# sr16_rx4_integ.lef : copie de sr16_rx4.lef pour l integration de MSPHY5973 (prompt-063-leo, 29/09/2026).
# Seul changement : CK_P et CK_N elargies de x 0,15 a 0,40 um vers l interieur, dans le couloir Metal3
# libre d obstruction (0 a 0,63 um). Le fil du routeur recouvre alors la vraie borne (0 a 0,15). Sans cela :
# DRT-0073 No access point for sr16_rx4/CK_N (coupe4). A remonter au generateur (Caelum).
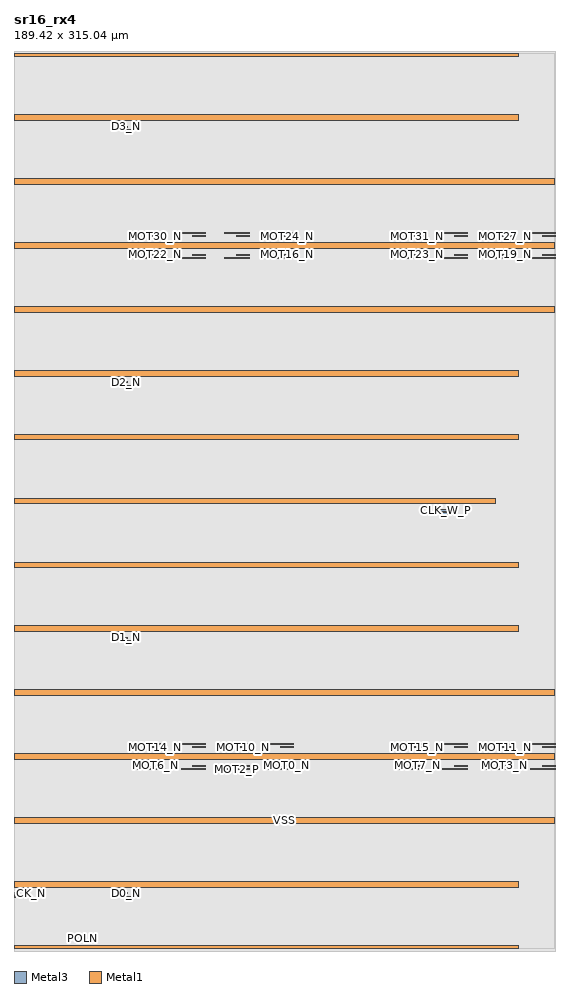
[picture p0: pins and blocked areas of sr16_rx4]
MACRO sr16_rx4
  CLASS BLOCK ;
  FOREIGN sr16_rx4 ;
  ORIGIN 0.150 1.000 ;
  SIZE 189.420 BY 315.040 ;
  PIN CK_N
    DIRECTION INPUT ;
    USE SIGNAL ;
    PORT
      LAYER Metal3 ;
        RECT 0.000 18.760 0.400 19.360 ;
    END
  END CK_N
  PIN CK_P
    DIRECTION INPUT ;
    USE SIGNAL ;
    PORT
      LAYER Metal3 ;
        RECT 0.000 17.660 0.400 18.260 ;
    END
  END CK_P
  PIN D0_N
    DIRECTION INPUT ;
    USE SIGNAL ;
    PORT
      LAYER Metal3 ;
        RECT 38.170 19.010 39.735 19.310 ;
    END
  END D0_N
  PIN D0_P
    DIRECTION INPUT ;
    USE SIGNAL ;
    PORT
      LAYER Metal3 ;
        RECT 38.170 17.910 41.980 18.210 ;
    END
  END D0_P
  PIN D1_N
    DIRECTION INPUT ;
    USE SIGNAL ;
    PORT
      LAYER Metal3 ;
        RECT 38.170 108.450 39.735 108.750 ;
    END
  END D1_N
  PIN D1_P
    DIRECTION INPUT ;
    USE SIGNAL ;
    PORT
      LAYER Metal3 ;
        RECT 38.170 107.350 41.980 107.650 ;
    END
  END D1_P
  PIN D2_N
    DIRECTION INPUT ;
    USE SIGNAL ;
    PORT
      LAYER Metal3 ;
        RECT 38.170 197.890 39.735 198.190 ;
    END
  END D2_N
  PIN D2_P
    DIRECTION INPUT ;
    USE SIGNAL ;
    PORT
      LAYER Metal3 ;
        RECT 38.170 196.790 41.980 197.090 ;
    END
  END D2_P
  PIN D3_N
    DIRECTION INPUT ;
    USE SIGNAL ;
    PORT
      LAYER Metal3 ;
        RECT 38.170 287.330 39.735 287.630 ;
    END
  END D3_N
  PIN D3_P
    DIRECTION INPUT ;
    USE SIGNAL ;
    PORT
      LAYER Metal3 ;
        RECT 38.170 286.230 41.980 286.530 ;
    END
  END D3_P
  PIN POLN
    DIRECTION INPUT ;
    USE SIGNAL ;
    PORT
      LAYER Metal3 ;
        RECT 23.370 3.010 24.040 4.030 ;
    END
  END POLN
  PIN MOT0_N
    DIRECTION OUTPUT ;
    USE SIGNAL ;
    PORT
      LAYER Metal3 ;
        RECT 93.050 63.480 97.590 64.080 ;
    END
  END MOT0_N
  PIN MOT0_P
    DIRECTION OUTPUT ;
    USE SIGNAL ;
    PORT
      LAYER Metal3 ;
        RECT 89.030 62.380 97.590 62.980 ;
    END
  END MOT0_P
  PIN MOT1_N
    DIRECTION OUTPUT ;
    USE SIGNAL ;
    PORT
      LAYER Metal3 ;
        RECT 184.730 63.480 189.270 64.080 ;
    END
  END MOT1_N
  PIN MOT1_P
    DIRECTION OUTPUT ;
    USE SIGNAL ;
    PORT
      LAYER Metal3 ;
        RECT 180.710 62.380 189.270 62.980 ;
    END
  END MOT1_P
  PIN MOT2_N
    DIRECTION OUTPUT ;
    USE SIGNAL ;
    PORT
      LAYER Metal3 ;
        RECT 77.690 63.480 82.230 64.080 ;
    END
  END MOT2_N
  PIN MOT2_P
    DIRECTION OUTPUT ;
    USE SIGNAL ;
    PORT
      LAYER Metal3 ;
        RECT 73.670 62.380 82.230 62.980 ;
    END
  END MOT2_P
  PIN MOT3_N
    DIRECTION OUTPUT ;
    USE SIGNAL ;
    PORT
      LAYER Metal3 ;
        RECT 169.370 63.480 173.910 64.080 ;
    END
  END MOT3_N
  PIN MOT3_P
    DIRECTION OUTPUT ;
    USE SIGNAL ;
    PORT
      LAYER Metal3 ;
        RECT 165.350 62.380 173.910 62.980 ;
    END
  END MOT3_P
  PIN MOT4_N
    DIRECTION OUTPUT ;
    USE SIGNAL ;
    PORT
      LAYER Metal3 ;
        RECT 62.330 63.480 66.870 64.080 ;
    END
  END MOT4_N
  PIN MOT4_P
    DIRECTION OUTPUT ;
    USE SIGNAL ;
    PORT
      LAYER Metal3 ;
        RECT 58.310 62.380 66.870 62.980 ;
    END
  END MOT4_P
  PIN MOT5_N
    DIRECTION OUTPUT ;
    USE SIGNAL ;
    PORT
      LAYER Metal3 ;
        RECT 154.010 63.480 158.550 64.080 ;
    END
  END MOT5_N
  PIN MOT5_P
    DIRECTION OUTPUT ;
    USE SIGNAL ;
    PORT
      LAYER Metal3 ;
        RECT 149.990 62.380 158.550 62.980 ;
    END
  END MOT5_P
  PIN MOT6_N
    DIRECTION OUTPUT ;
    USE SIGNAL ;
    PORT
      LAYER Metal3 ;
        RECT 46.970 63.480 51.510 64.080 ;
    END
  END MOT6_N
  PIN MOT6_P
    DIRECTION OUTPUT ;
    USE SIGNAL ;
    PORT
      LAYER Metal3 ;
        RECT 42.950 62.380 51.510 62.980 ;
    END
  END MOT6_P
  PIN MOT7_N
    DIRECTION OUTPUT ;
    USE SIGNAL ;
    PORT
      LAYER Metal3 ;
        RECT 138.650 63.480 143.190 64.080 ;
    END
  END MOT7_N
  PIN MOT7_P
    DIRECTION OUTPUT ;
    USE SIGNAL ;
    PORT
      LAYER Metal3 ;
        RECT 134.630 62.380 143.190 62.980 ;
    END
  END MOT7_P
  PIN MOT8_N
    DIRECTION OUTPUT ;
    USE SIGNAL ;
    PORT
      LAYER Metal3 ;
        RECT 93.050 70.080 97.590 70.680 ;
    END
  END MOT8_N
  PIN MOT8_P
    DIRECTION OUTPUT ;
    USE SIGNAL ;
    PORT
      LAYER Metal3 ;
        RECT 89.030 71.180 97.590 71.780 ;
    END
  END MOT8_P
  PIN MOT9_N
    DIRECTION OUTPUT ;
    USE SIGNAL ;
    PORT
      LAYER Metal3 ;
        RECT 184.730 70.080 189.270 70.680 ;
    END
  END MOT9_N
  PIN MOT9_P
    DIRECTION OUTPUT ;
    USE SIGNAL ;
    PORT
      LAYER Metal3 ;
        RECT 180.710 71.180 189.270 71.780 ;
    END
  END MOT9_P
  PIN MOT10_N
    DIRECTION OUTPUT ;
    USE SIGNAL ;
    PORT
      LAYER Metal3 ;
        RECT 77.690 70.080 82.230 70.680 ;
    END
  END MOT10_N
  PIN MOT10_P
    DIRECTION OUTPUT ;
    USE SIGNAL ;
    PORT
      LAYER Metal3 ;
        RECT 73.670 71.180 82.230 71.780 ;
    END
  END MOT10_P
  PIN MOT11_N
    DIRECTION OUTPUT ;
    USE SIGNAL ;
    PORT
      LAYER Metal3 ;
        RECT 169.370 70.080 173.910 70.680 ;
    END
  END MOT11_N
  PIN MOT11_P
    DIRECTION OUTPUT ;
    USE SIGNAL ;
    PORT
      LAYER Metal3 ;
        RECT 165.350 71.180 173.910 71.780 ;
    END
  END MOT11_P
  PIN MOT12_N
    DIRECTION OUTPUT ;
    USE SIGNAL ;
    PORT
      LAYER Metal3 ;
        RECT 62.330 70.080 66.870 70.680 ;
    END
  END MOT12_N
  PIN MOT12_P
    DIRECTION OUTPUT ;
    USE SIGNAL ;
    PORT
      LAYER Metal3 ;
        RECT 58.310 71.180 66.870 71.780 ;
    END
  END MOT12_P
  PIN MOT13_N
    DIRECTION OUTPUT ;
    USE SIGNAL ;
    PORT
      LAYER Metal3 ;
        RECT 154.010 70.080 158.550 70.680 ;
    END
  END MOT13_N
  PIN MOT13_P
    DIRECTION OUTPUT ;
    USE SIGNAL ;
    PORT
      LAYER Metal3 ;
        RECT 149.990 71.180 158.550 71.780 ;
    END
  END MOT13_P
  PIN MOT14_N
    DIRECTION OUTPUT ;
    USE SIGNAL ;
    PORT
      LAYER Metal3 ;
        RECT 46.970 70.080 51.510 70.680 ;
    END
  END MOT14_N
  PIN MOT14_P
    DIRECTION OUTPUT ;
    USE SIGNAL ;
    PORT
      LAYER Metal3 ;
        RECT 42.950 71.180 51.510 71.780 ;
    END
  END MOT14_P
  PIN MOT15_N
    DIRECTION OUTPUT ;
    USE SIGNAL ;
    PORT
      LAYER Metal3 ;
        RECT 138.650 70.080 143.190 70.680 ;
    END
  END MOT15_N
  PIN MOT15_P
    DIRECTION OUTPUT ;
    USE SIGNAL ;
    PORT
      LAYER Metal3 ;
        RECT 134.630 71.180 143.190 71.780 ;
    END
  END MOT15_P
  PIN MOT16_N
    DIRECTION OUTPUT ;
    USE SIGNAL ;
    PORT
      LAYER Metal3 ;
        RECT 93.050 242.360 97.590 242.960 ;
    END
  END MOT16_N
  PIN MOT16_P
    DIRECTION OUTPUT ;
    USE SIGNAL ;
    PORT
      LAYER Metal3 ;
        RECT 89.030 241.260 97.590 241.860 ;
    END
  END MOT16_P
  PIN MOT17_N
    DIRECTION OUTPUT ;
    USE SIGNAL ;
    PORT
      LAYER Metal3 ;
        RECT 184.730 242.360 189.270 242.960 ;
    END
  END MOT17_N
  PIN MOT17_P
    DIRECTION OUTPUT ;
    USE SIGNAL ;
    PORT
      LAYER Metal3 ;
        RECT 180.710 241.260 189.270 241.860 ;
    END
  END MOT17_P
  PIN MOT18_N
    DIRECTION OUTPUT ;
    USE SIGNAL ;
    PORT
      LAYER Metal3 ;
        RECT 77.690 242.360 82.230 242.960 ;
    END
  END MOT18_N
  PIN MOT18_P
    DIRECTION OUTPUT ;
    USE SIGNAL ;
    PORT
      LAYER Metal3 ;
        RECT 73.670 241.260 82.230 241.860 ;
    END
  END MOT18_P
  PIN MOT19_N
    DIRECTION OUTPUT ;
    USE SIGNAL ;
    PORT
      LAYER Metal3 ;
        RECT 169.370 242.360 173.910 242.960 ;
    END
  END MOT19_N
  PIN MOT19_P
    DIRECTION OUTPUT ;
    USE SIGNAL ;
    PORT
      LAYER Metal3 ;
        RECT 165.350 241.260 173.910 241.860 ;
    END
  END MOT19_P
  PIN MOT20_N
    DIRECTION OUTPUT ;
    USE SIGNAL ;
    PORT
      LAYER Metal3 ;
        RECT 62.330 242.360 66.870 242.960 ;
    END
  END MOT20_N
  PIN MOT20_P
    DIRECTION OUTPUT ;
    USE SIGNAL ;
    PORT
      LAYER Metal3 ;
        RECT 58.310 241.260 66.870 241.860 ;
    END
  END MOT20_P
  PIN MOT21_N
    DIRECTION OUTPUT ;
    USE SIGNAL ;
    PORT
      LAYER Metal3 ;
        RECT 154.010 242.360 158.550 242.960 ;
    END
  END MOT21_N
  PIN MOT21_P
    DIRECTION OUTPUT ;
    USE SIGNAL ;
    PORT
      LAYER Metal3 ;
        RECT 149.990 241.260 158.550 241.860 ;
    END
  END MOT21_P
  PIN MOT22_N
    DIRECTION OUTPUT ;
    USE SIGNAL ;
    PORT
      LAYER Metal3 ;
        RECT 46.970 242.360 51.510 242.960 ;
    END
  END MOT22_N
  PIN MOT22_P
    DIRECTION OUTPUT ;
    USE SIGNAL ;
    PORT
      LAYER Metal3 ;
        RECT 42.950 241.260 51.510 241.860 ;
    END
  END MOT22_P
  PIN MOT23_N
    DIRECTION OUTPUT ;
    USE SIGNAL ;
    PORT
      LAYER Metal3 ;
        RECT 138.650 242.360 143.190 242.960 ;
    END
  END MOT23_N
  PIN MOT23_P
    DIRECTION OUTPUT ;
    USE SIGNAL ;
    PORT
      LAYER Metal3 ;
        RECT 134.630 241.260 143.190 241.860 ;
    END
  END MOT23_P
  PIN MOT24_N
    DIRECTION OUTPUT ;
    USE SIGNAL ;
    PORT
      LAYER Metal3 ;
        RECT 93.050 248.960 97.590 249.560 ;
    END
  END MOT24_N
  PIN MOT24_P
    DIRECTION OUTPUT ;
    USE SIGNAL ;
    PORT
      LAYER Metal3 ;
        RECT 89.030 250.060 97.590 250.660 ;
    END
  END MOT24_P
  PIN MOT25_N
    DIRECTION OUTPUT ;
    USE SIGNAL ;
    PORT
      LAYER Metal3 ;
        RECT 184.730 248.960 189.270 249.560 ;
    END
  END MOT25_N
  PIN MOT25_P
    DIRECTION OUTPUT ;
    USE SIGNAL ;
    PORT
      LAYER Metal3 ;
        RECT 180.710 250.060 189.270 250.660 ;
    END
  END MOT25_P
  PIN MOT26_N
    DIRECTION OUTPUT ;
    USE SIGNAL ;
    PORT
      LAYER Metal3 ;
        RECT 77.690 248.960 82.230 249.560 ;
    END
  END MOT26_N
  PIN MOT26_P
    DIRECTION OUTPUT ;
    USE SIGNAL ;
    PORT
      LAYER Metal3 ;
        RECT 73.670 250.060 82.230 250.660 ;
    END
  END MOT26_P
  PIN MOT27_N
    DIRECTION OUTPUT ;
    USE SIGNAL ;
    PORT
      LAYER Metal3 ;
        RECT 169.370 248.960 173.910 249.560 ;
    END
  END MOT27_N
  PIN MOT27_P
    DIRECTION OUTPUT ;
    USE SIGNAL ;
    PORT
      LAYER Metal3 ;
        RECT 165.350 250.060 173.910 250.660 ;
    END
  END MOT27_P
  PIN MOT28_N
    DIRECTION OUTPUT ;
    USE SIGNAL ;
    PORT
      LAYER Metal3 ;
        RECT 62.330 248.960 66.870 249.560 ;
    END
  END MOT28_N
  PIN MOT28_P
    DIRECTION OUTPUT ;
    USE SIGNAL ;
    PORT
      LAYER Metal3 ;
        RECT 58.310 250.060 66.870 250.660 ;
    END
  END MOT28_P
  PIN MOT29_N
    DIRECTION OUTPUT ;
    USE SIGNAL ;
    PORT
      LAYER Metal3 ;
        RECT 154.010 248.960 158.550 249.560 ;
    END
  END MOT29_N
  PIN MOT29_P
    DIRECTION OUTPUT ;
    USE SIGNAL ;
    PORT
      LAYER Metal3 ;
        RECT 149.990 250.060 158.550 250.660 ;
    END
  END MOT29_P
  PIN MOT30_N
    DIRECTION OUTPUT ;
    USE SIGNAL ;
    PORT
      LAYER Metal3 ;
        RECT 46.970 248.960 51.510 249.560 ;
    END
  END MOT30_N
  PIN MOT30_P
    DIRECTION OUTPUT ;
    USE SIGNAL ;
    PORT
      LAYER Metal3 ;
        RECT 42.950 250.060 51.510 250.660 ;
    END
  END MOT30_P
  PIN MOT31_N
    DIRECTION OUTPUT ;
    USE SIGNAL ;
    PORT
      LAYER Metal3 ;
        RECT 138.650 248.960 143.190 249.560 ;
    END
  END MOT31_N
  PIN MOT31_P
    DIRECTION OUTPUT ;
    USE SIGNAL ;
    PORT
      LAYER Metal3 ;
        RECT 134.630 250.060 143.190 250.660 ;
    END
  END MOT31_P
  PIN CLK_W_N
    DIRECTION OUTPUT ;
    USE SIGNAL ;
    PORT
      LAYER Metal3 ;
        RECT 144.630 151.820 153.190 152.420 ;
    END
  END CLK_W_N
  PIN CLK_W_P
    DIRECTION OUTPUT ;
    USE SIGNAL ;
    PORT
      LAYER Metal3 ;
        RECT 148.650 152.920 153.190 153.520 ;
    END
  END CLK_W_P
  PIN VDD
    DIRECTION INOUT ;
    USE POWER ;
    PORT
      LAYER Metal1 ;
        RECT 0.000 21.360 176.560 23.360 ;
        RECT 0.000 66.080 189.120 68.080 ;
        RECT 0.000 110.800 176.560 112.800 ;
        RECT 0.000 155.520 168.400 157.520 ;
        RECT 0.000 200.240 176.560 202.240 ;
        RECT 0.000 244.960 189.120 246.960 ;
        RECT 0.000 289.680 176.560 291.680 ;
    END
  END VDD
  PIN VSS
    DIRECTION INOUT ;
    USE GROUND ;
    PORT
      LAYER Metal1 ;
        RECT 0.000 0.000 176.560 1.000 ;
        RECT 0.000 43.720 189.120 45.720 ;
        RECT 0.000 88.440 189.120 90.440 ;
        RECT 0.000 133.160 176.560 135.160 ;
        RECT 0.000 177.880 176.560 179.880 ;
        RECT 0.000 222.600 189.120 224.600 ;
        RECT 0.000 267.320 189.120 269.320 ;
        RECT 0.000 312.040 176.560 313.040 ;
    END
  END VSS
  OBS
    LAYER Metal1 ;
      RECT -0.150 -1.000 189.270 0.000 ;
      RECT -0.150 0.000 0.000 1.000 ;
      RECT 176.560 0.000 189.270 1.000 ;
      RECT -0.150 1.000 189.270 21.360 ;
      RECT -0.150 21.360 0.000 23.360 ;
      RECT 176.560 21.360 189.270 23.360 ;
      RECT -0.150 23.360 189.270 43.720 ;
      RECT -0.150 43.720 0.000 45.720 ;
      RECT 189.120 43.720 189.270 45.720 ;
      RECT -0.150 45.720 189.270 66.080 ;
      RECT -0.150 66.080 0.000 68.080 ;
      RECT 189.120 66.080 189.270 68.080 ;
      RECT -0.150 68.080 189.270 88.440 ;
      RECT -0.150 88.440 0.000 90.440 ;
      RECT 189.120 88.440 189.270 90.440 ;
      RECT -0.150 90.440 189.270 110.800 ;
      RECT -0.150 110.800 0.000 112.800 ;
      RECT 176.560 110.800 189.270 112.800 ;
      RECT -0.150 112.800 189.270 133.160 ;
      RECT -0.150 133.160 0.000 135.160 ;
      RECT 176.560 133.160 189.270 135.160 ;
      RECT -0.150 135.160 189.270 155.520 ;
      RECT -0.150 155.520 0.000 157.520 ;
      RECT 168.400 155.520 189.270 157.520 ;
      RECT -0.150 157.520 189.270 177.880 ;
      RECT -0.150 177.880 0.000 179.880 ;
      RECT 176.560 177.880 189.270 179.880 ;
      RECT -0.150 179.880 189.270 200.240 ;
      RECT -0.150 200.240 0.000 202.240 ;
      RECT 176.560 200.240 189.270 202.240 ;
      RECT -0.150 202.240 189.270 222.600 ;
      RECT -0.150 222.600 0.000 224.600 ;
      RECT 189.120 222.600 189.270 224.600 ;
      RECT -0.150 224.600 189.270 244.960 ;
      RECT -0.150 244.960 0.000 246.960 ;
      RECT 189.120 244.960 189.270 246.960 ;
      RECT -0.150 246.960 189.270 267.320 ;
      RECT -0.150 267.320 0.000 269.320 ;
      RECT 189.120 267.320 189.270 269.320 ;
      RECT -0.150 269.320 189.270 289.680 ;
      RECT -0.150 289.680 0.000 291.680 ;
      RECT 176.560 289.680 189.270 291.680 ;
      RECT -0.150 291.680 189.270 312.040 ;
      RECT -0.150 312.040 0.000 313.040 ;
      RECT 176.560 312.040 189.270 313.040 ;
      RECT -0.150 313.040 189.270 314.040 ;
    LAYER Metal2 ;
      RECT 75.375 133.360 104.650 133.660 ;
      RECT -0.150 -1.000 189.270 0.000 ;
      RECT -0.150 0.000 0.000 1.000 ;
      RECT 176.560 0.000 189.270 1.000 ;
      RECT -0.150 1.000 189.270 21.360 ;
      RECT -0.150 21.360 0.000 23.360 ;
      RECT 176.560 21.360 189.270 23.360 ;
      RECT -0.150 23.360 189.270 43.720 ;
      RECT -0.150 43.720 0.000 45.720 ;
      RECT 189.120 43.720 189.270 45.720 ;
      RECT -0.150 45.720 189.270 66.080 ;
      RECT -0.150 66.080 0.000 68.080 ;
      RECT 189.120 66.080 189.270 68.080 ;
      RECT -0.150 68.080 189.270 88.440 ;
      RECT -0.150 88.440 0.000 90.440 ;
      RECT 189.120 88.440 189.270 90.440 ;
      RECT -0.150 90.440 189.270 110.800 ;
      RECT -0.150 110.800 0.000 112.800 ;
      RECT 176.560 110.800 189.270 112.800 ;
      RECT -0.150 112.800 189.270 133.160 ;
      RECT -0.150 133.160 0.000 135.160 ;
      RECT 176.560 133.160 189.270 135.160 ;
      RECT -0.150 135.160 189.270 155.520 ;
      RECT -0.150 155.520 0.000 157.520 ;
      RECT 168.400 155.520 189.270 157.520 ;
      RECT -0.150 157.520 189.270 177.880 ;
      RECT -0.150 177.880 0.000 179.880 ;
      RECT 176.560 177.880 189.270 179.880 ;
      RECT -0.150 179.880 189.270 200.240 ;
      RECT -0.150 200.240 0.000 202.240 ;
      RECT 176.560 200.240 189.270 202.240 ;
      RECT -0.150 202.240 189.270 222.600 ;
      RECT -0.150 222.600 0.000 224.600 ;
      RECT 189.120 222.600 189.270 224.600 ;
      RECT -0.150 224.600 189.270 244.960 ;
      RECT -0.150 244.960 0.000 246.960 ;
      RECT 189.120 244.960 189.270 246.960 ;
      RECT -0.150 246.960 189.270 267.320 ;
      RECT -0.150 267.320 0.000 269.320 ;
      RECT 189.120 267.320 189.270 269.320 ;
      RECT -0.150 269.320 189.270 289.680 ;
      RECT -0.150 289.680 0.000 291.680 ;
      RECT 176.560 289.680 189.270 291.680 ;
      RECT -0.150 291.680 189.270 312.040 ;
      RECT -0.150 312.040 0.000 313.040 ;
      RECT 176.560 312.040 189.270 313.040 ;
      RECT -0.150 313.040 189.270 314.040 ;
    LAYER Metal3 ;
      RECT -0.150 -1.000 189.270 0.000 ;
      RECT -0.150 0.000 0.000 1.000 ;
      RECT 176.560 0.000 189.270 1.000 ;
      RECT -0.150 1.000 189.270 2.530 ;
      RECT -0.150 2.530 22.890 4.510 ;
      RECT 24.520 2.530 189.270 4.510 ;
      RECT -0.150 4.510 189.270 17.180 ;
      RECT 0.630 17.180 189.270 17.430 ;
      RECT 0.630 17.430 37.690 18.280 ;
      RECT 42.460 17.430 189.270 18.280 ;
      RECT 0.630 18.280 37.690 18.530 ;
      RECT 42.460 18.280 189.270 18.530 ;
      RECT 0.630 18.530 37.690 18.690 ;
      RECT 42.460 18.530 189.270 18.690 ;
      RECT 0.630 18.690 37.690 18.740 ;
      RECT 40.215 18.690 189.270 18.740 ;
      RECT 0.630 18.740 37.690 19.790 ;
      RECT 40.215 18.740 189.270 19.790 ;
      RECT 0.630 19.790 189.270 19.840 ;
      RECT -0.150 19.840 189.270 21.360 ;
      RECT -0.150 21.360 0.000 23.360 ;
      RECT 176.560 21.360 189.270 23.360 ;
      RECT -0.150 23.360 189.270 43.720 ;
      RECT -0.150 43.720 0.000 45.720 ;
      RECT 189.120 43.720 189.270 45.720 ;
      RECT -0.150 45.720 189.270 61.900 ;
      RECT -0.150 61.900 42.470 63.000 ;
      RECT 51.990 61.900 57.830 63.000 ;
      RECT 67.350 61.900 73.190 63.000 ;
      RECT 82.710 61.900 88.550 63.000 ;
      RECT 98.070 61.900 134.150 63.000 ;
      RECT 143.670 61.900 149.510 63.000 ;
      RECT 159.030 61.900 164.870 63.000 ;
      RECT 174.390 61.900 180.230 63.000 ;
      RECT -0.150 63.000 42.470 63.460 ;
      RECT 51.990 63.000 57.830 63.460 ;
      RECT 67.350 63.000 73.190 63.460 ;
      RECT 82.710 63.000 88.550 63.460 ;
      RECT 98.070 63.000 134.150 63.460 ;
      RECT 143.670 63.000 149.510 63.460 ;
      RECT 159.030 63.000 164.870 63.460 ;
      RECT 174.390 63.000 180.230 63.460 ;
      RECT -0.150 63.460 46.490 64.560 ;
      RECT 51.990 63.460 61.850 64.560 ;
      RECT 67.350 63.460 77.210 64.560 ;
      RECT 82.710 63.460 92.570 64.560 ;
      RECT 98.070 63.460 138.170 64.560 ;
      RECT 143.670 63.460 153.530 64.560 ;
      RECT 159.030 63.460 168.890 64.560 ;
      RECT 174.390 63.460 184.250 64.560 ;
      RECT -0.150 64.560 189.270 66.080 ;
      RECT -0.150 66.080 0.000 68.080 ;
      RECT 189.120 66.080 189.270 68.080 ;
      RECT -0.150 68.080 189.270 69.600 ;
      RECT -0.150 69.600 46.490 70.700 ;
      RECT 51.990 69.600 61.850 70.700 ;
      RECT 67.350 69.600 77.210 70.700 ;
      RECT 82.710 69.600 92.570 70.700 ;
      RECT 98.070 69.600 138.170 70.700 ;
      RECT 143.670 69.600 153.530 70.700 ;
      RECT 159.030 69.600 168.890 70.700 ;
      RECT 174.390 69.600 184.250 70.700 ;
      RECT -0.150 70.700 42.470 71.160 ;
      RECT 51.990 70.700 57.830 71.160 ;
      RECT 67.350 70.700 73.190 71.160 ;
      RECT 82.710 70.700 88.550 71.160 ;
      RECT 98.070 70.700 134.150 71.160 ;
      RECT 143.670 70.700 149.510 71.160 ;
      RECT 159.030 70.700 164.870 71.160 ;
      RECT 174.390 70.700 180.230 71.160 ;
      RECT -0.150 71.160 42.470 72.260 ;
      RECT 51.990 71.160 57.830 72.260 ;
      RECT 67.350 71.160 73.190 72.260 ;
      RECT 82.710 71.160 88.550 72.260 ;
      RECT 98.070 71.160 134.150 72.260 ;
      RECT 143.670 71.160 149.510 72.260 ;
      RECT 159.030 71.160 164.870 72.260 ;
      RECT 174.390 71.160 180.230 72.260 ;
      RECT -0.150 72.260 189.270 88.440 ;
      RECT -0.150 88.440 0.000 90.440 ;
      RECT 189.120 88.440 189.270 90.440 ;
      RECT -0.150 90.440 189.270 106.870 ;
      RECT -0.150 106.870 37.690 107.970 ;
      RECT 42.460 106.870 189.270 107.970 ;
      RECT -0.150 107.970 37.690 108.130 ;
      RECT 42.460 107.970 189.270 108.130 ;
      RECT -0.150 108.130 37.690 109.230 ;
      RECT 40.215 108.130 189.270 109.230 ;
      RECT -0.150 109.230 189.270 110.800 ;
      RECT -0.150 110.800 0.000 112.800 ;
      RECT 176.560 110.800 189.270 112.800 ;
      RECT -0.150 112.800 189.270 133.160 ;
      RECT -0.150 133.160 0.000 135.160 ;
      RECT 176.560 133.160 189.270 135.160 ;
      RECT -0.150 135.160 189.270 151.340 ;
      RECT -0.150 151.340 144.150 152.440 ;
      RECT 153.670 151.340 189.270 152.440 ;
      RECT -0.150 152.440 144.150 152.900 ;
      RECT 153.670 152.440 189.270 152.900 ;
      RECT -0.150 152.900 148.170 154.000 ;
      RECT 153.670 152.900 189.270 154.000 ;
      RECT -0.150 154.000 189.270 155.520 ;
      RECT -0.150 155.520 0.000 157.520 ;
      RECT 168.400 155.520 189.270 157.520 ;
      RECT -0.150 157.520 189.270 177.880 ;
      RECT -0.150 177.880 0.000 179.880 ;
      RECT 176.560 177.880 189.270 179.880 ;
      RECT -0.150 179.880 189.270 196.310 ;
      RECT -0.150 196.310 37.690 197.410 ;
      RECT 42.460 196.310 189.270 197.410 ;
      RECT -0.150 197.410 37.690 197.570 ;
      RECT 42.460 197.410 189.270 197.570 ;
      RECT -0.150 197.570 37.690 198.670 ;
      RECT 40.215 197.570 189.270 198.670 ;
      RECT -0.150 198.670 189.270 200.240 ;
      RECT -0.150 200.240 0.000 202.240 ;
      RECT 176.560 200.240 189.270 202.240 ;
      RECT -0.150 202.240 189.270 222.600 ;
      RECT -0.150 222.600 0.000 224.600 ;
      RECT 189.120 222.600 189.270 224.600 ;
      RECT -0.150 224.600 189.270 240.780 ;
      RECT -0.150 240.780 42.470 241.880 ;
      RECT 51.990 240.780 57.830 241.880 ;
      RECT 67.350 240.780 73.190 241.880 ;
      RECT 82.710 240.780 88.550 241.880 ;
      RECT 98.070 240.780 134.150 241.880 ;
      RECT 143.670 240.780 149.510 241.880 ;
      RECT 159.030 240.780 164.870 241.880 ;
      RECT 174.390 240.780 180.230 241.880 ;
      RECT -0.150 241.880 42.470 242.340 ;
      RECT 51.990 241.880 57.830 242.340 ;
      RECT 67.350 241.880 73.190 242.340 ;
      RECT 82.710 241.880 88.550 242.340 ;
      RECT 98.070 241.880 134.150 242.340 ;
      RECT 143.670 241.880 149.510 242.340 ;
      RECT 159.030 241.880 164.870 242.340 ;
      RECT 174.390 241.880 180.230 242.340 ;
      RECT -0.150 242.340 46.490 243.440 ;
      RECT 51.990 242.340 61.850 243.440 ;
      RECT 67.350 242.340 77.210 243.440 ;
      RECT 82.710 242.340 92.570 243.440 ;
      RECT 98.070 242.340 138.170 243.440 ;
      RECT 143.670 242.340 153.530 243.440 ;
      RECT 159.030 242.340 168.890 243.440 ;
      RECT 174.390 242.340 184.250 243.440 ;
      RECT -0.150 243.440 189.270 244.960 ;
      RECT -0.150 244.960 0.000 246.960 ;
      RECT 189.120 244.960 189.270 246.960 ;
      RECT -0.150 246.960 189.270 248.480 ;
      RECT -0.150 248.480 46.490 249.580 ;
      RECT 51.990 248.480 61.850 249.580 ;
      RECT 67.350 248.480 77.210 249.580 ;
      RECT 82.710 248.480 92.570 249.580 ;
      RECT 98.070 248.480 138.170 249.580 ;
      RECT 143.670 248.480 153.530 249.580 ;
      RECT 159.030 248.480 168.890 249.580 ;
      RECT 174.390 248.480 184.250 249.580 ;
      RECT -0.150 249.580 42.470 250.040 ;
      RECT 51.990 249.580 57.830 250.040 ;
      RECT 67.350 249.580 73.190 250.040 ;
      RECT 82.710 249.580 88.550 250.040 ;
      RECT 98.070 249.580 134.150 250.040 ;
      RECT 143.670 249.580 149.510 250.040 ;
      RECT 159.030 249.580 164.870 250.040 ;
      RECT 174.390 249.580 180.230 250.040 ;
      RECT -0.150 250.040 42.470 251.140 ;
      RECT 51.990 250.040 57.830 251.140 ;
      RECT 67.350 250.040 73.190 251.140 ;
      RECT 82.710 250.040 88.550 251.140 ;
      RECT 98.070 250.040 134.150 251.140 ;
      RECT 143.670 250.040 149.510 251.140 ;
      RECT 159.030 250.040 164.870 251.140 ;
      RECT 174.390 250.040 180.230 251.140 ;
      RECT -0.150 251.140 189.270 267.320 ;
      RECT -0.150 267.320 0.000 269.320 ;
      RECT 189.120 267.320 189.270 269.320 ;
      RECT -0.150 269.320 189.270 285.750 ;
      RECT -0.150 285.750 37.690 286.850 ;
      RECT 42.460 285.750 189.270 286.850 ;
      RECT -0.150 286.850 37.690 287.010 ;
      RECT 42.460 286.850 189.270 287.010 ;
      RECT -0.150 287.010 37.690 288.110 ;
      RECT 40.215 287.010 189.270 288.110 ;
      RECT -0.150 288.110 189.270 289.680 ;
      RECT -0.150 289.680 0.000 291.680 ;
      RECT 176.560 289.680 189.270 291.680 ;
      RECT -0.150 291.680 189.270 312.040 ;
      RECT -0.150 312.040 0.000 313.040 ;
      RECT 176.560 312.040 189.270 313.040 ;
      RECT -0.150 313.040 189.270 314.040 ;
    LAYER Metal4 ;
      RECT -0.150 -1.000 189.270 0.000 ;
      RECT -0.150 0.000 0.000 1.000 ;
      RECT 176.560 0.000 189.270 1.000 ;
      RECT -0.150 1.000 189.270 2.530 ;
      RECT -0.150 2.530 22.890 4.510 ;
      RECT 24.520 2.530 189.270 4.510 ;
      RECT -0.150 4.510 189.270 17.180 ;
      RECT 0.630 17.180 189.270 17.430 ;
      RECT 0.630 17.430 37.690 18.280 ;
      RECT 42.460 17.430 189.270 18.280 ;
      RECT 0.630 18.280 37.690 18.530 ;
      RECT 42.460 18.280 189.270 18.530 ;
      RECT 0.630 18.530 37.690 18.690 ;
      RECT 42.460 18.530 189.270 18.690 ;
      RECT 0.630 18.690 37.690 18.740 ;
      RECT 40.215 18.690 189.270 18.740 ;
      RECT 0.630 18.740 37.690 19.790 ;
      RECT 40.215 18.740 189.270 19.790 ;
      RECT 0.630 19.790 189.270 19.840 ;
      RECT -0.150 19.840 189.270 21.360 ;
      RECT -0.150 21.360 0.000 23.360 ;
      RECT 176.560 21.360 189.270 23.360 ;
      RECT -0.150 23.360 189.270 43.720 ;
      RECT -0.150 43.720 0.000 45.720 ;
      RECT 189.120 43.720 189.270 45.720 ;
      RECT -0.150 45.720 189.270 61.900 ;
      RECT -0.150 61.900 42.470 63.000 ;
      RECT 51.990 61.900 57.830 63.000 ;
      RECT 67.350 61.900 73.190 63.000 ;
      RECT 82.710 61.900 88.550 63.000 ;
      RECT 98.070 61.900 134.150 63.000 ;
      RECT 143.670 61.900 149.510 63.000 ;
      RECT 159.030 61.900 164.870 63.000 ;
      RECT 174.390 61.900 180.230 63.000 ;
      RECT -0.150 63.000 42.470 63.460 ;
      RECT 51.990 63.000 57.830 63.460 ;
      RECT 67.350 63.000 73.190 63.460 ;
      RECT 82.710 63.000 88.550 63.460 ;
      RECT 98.070 63.000 134.150 63.460 ;
      RECT 143.670 63.000 149.510 63.460 ;
      RECT 159.030 63.000 164.870 63.460 ;
      RECT 174.390 63.000 180.230 63.460 ;
      RECT -0.150 63.460 46.490 64.560 ;
      RECT 51.990 63.460 61.850 64.560 ;
      RECT 67.350 63.460 77.210 64.560 ;
      RECT 82.710 63.460 92.570 64.560 ;
      RECT 98.070 63.460 138.170 64.560 ;
      RECT 143.670 63.460 153.530 64.560 ;
      RECT 159.030 63.460 168.890 64.560 ;
      RECT 174.390 63.460 184.250 64.560 ;
      RECT -0.150 64.560 189.270 66.080 ;
      RECT -0.150 66.080 0.000 68.080 ;
      RECT 189.120 66.080 189.270 68.080 ;
      RECT -0.150 68.080 189.270 69.600 ;
      RECT -0.150 69.600 46.490 70.700 ;
      RECT 51.990 69.600 61.850 70.700 ;
      RECT 67.350 69.600 77.210 70.700 ;
      RECT 82.710 69.600 92.570 70.700 ;
      RECT 98.070 69.600 138.170 70.700 ;
      RECT 143.670 69.600 153.530 70.700 ;
      RECT 159.030 69.600 168.890 70.700 ;
      RECT 174.390 69.600 184.250 70.700 ;
      RECT -0.150 70.700 42.470 71.160 ;
      RECT 51.990 70.700 57.830 71.160 ;
      RECT 67.350 70.700 73.190 71.160 ;
      RECT 82.710 70.700 88.550 71.160 ;
      RECT 98.070 70.700 134.150 71.160 ;
      RECT 143.670 70.700 149.510 71.160 ;
      RECT 159.030 70.700 164.870 71.160 ;
      RECT 174.390 70.700 180.230 71.160 ;
      RECT -0.150 71.160 42.470 72.260 ;
      RECT 51.990 71.160 57.830 72.260 ;
      RECT 67.350 71.160 73.190 72.260 ;
      RECT 82.710 71.160 88.550 72.260 ;
      RECT 98.070 71.160 134.150 72.260 ;
      RECT 143.670 71.160 149.510 72.260 ;
      RECT 159.030 71.160 164.870 72.260 ;
      RECT 174.390 71.160 180.230 72.260 ;
      RECT -0.150 72.260 189.270 88.440 ;
      RECT -0.150 88.440 0.000 90.440 ;
      RECT 189.120 88.440 189.270 90.440 ;
      RECT -0.150 90.440 189.270 106.870 ;
      RECT -0.150 106.870 37.690 107.970 ;
      RECT 42.460 106.870 189.270 107.970 ;
      RECT -0.150 107.970 37.690 108.130 ;
      RECT 42.460 107.970 189.270 108.130 ;
      RECT -0.150 108.130 37.690 109.230 ;
      RECT 40.215 108.130 189.270 109.230 ;
      RECT -0.150 109.230 189.270 110.800 ;
      RECT -0.150 110.800 0.000 112.800 ;
      RECT 176.560 110.800 189.270 112.800 ;
      RECT -0.150 112.800 189.270 133.160 ;
      RECT -0.150 133.160 0.000 135.160 ;
      RECT 176.560 133.160 189.270 135.160 ;
      RECT -0.150 135.160 189.270 151.340 ;
      RECT -0.150 151.340 144.150 152.440 ;
      RECT 153.670 151.340 189.270 152.440 ;
      RECT -0.150 152.440 144.150 152.900 ;
      RECT 153.670 152.440 189.270 152.900 ;
      RECT -0.150 152.900 148.170 154.000 ;
      RECT 153.670 152.900 189.270 154.000 ;
      RECT -0.150 154.000 189.270 155.520 ;
      RECT -0.150 155.520 0.000 157.520 ;
      RECT 168.400 155.520 189.270 157.520 ;
      RECT -0.150 157.520 189.270 177.880 ;
      RECT -0.150 177.880 0.000 179.880 ;
      RECT 176.560 177.880 189.270 179.880 ;
      RECT -0.150 179.880 189.270 196.310 ;
      RECT -0.150 196.310 37.690 197.410 ;
      RECT 42.460 196.310 189.270 197.410 ;
      RECT -0.150 197.410 37.690 197.570 ;
      RECT 42.460 197.410 189.270 197.570 ;
      RECT -0.150 197.570 37.690 198.670 ;
      RECT 40.215 197.570 189.270 198.670 ;
      RECT -0.150 198.670 189.270 200.240 ;
      RECT -0.150 200.240 0.000 202.240 ;
      RECT 176.560 200.240 189.270 202.240 ;
      RECT -0.150 202.240 189.270 222.600 ;
      RECT -0.150 222.600 0.000 224.600 ;
      RECT 189.120 222.600 189.270 224.600 ;
      RECT -0.150 224.600 189.270 240.780 ;
      RECT -0.150 240.780 42.470 241.880 ;
      RECT 51.990 240.780 57.830 241.880 ;
      RECT 67.350 240.780 73.190 241.880 ;
      RECT 82.710 240.780 88.550 241.880 ;
      RECT 98.070 240.780 134.150 241.880 ;
      RECT 143.670 240.780 149.510 241.880 ;
      RECT 159.030 240.780 164.870 241.880 ;
      RECT 174.390 240.780 180.230 241.880 ;
      RECT -0.150 241.880 42.470 242.340 ;
      RECT 51.990 241.880 57.830 242.340 ;
      RECT 67.350 241.880 73.190 242.340 ;
      RECT 82.710 241.880 88.550 242.340 ;
      RECT 98.070 241.880 134.150 242.340 ;
      RECT 143.670 241.880 149.510 242.340 ;
      RECT 159.030 241.880 164.870 242.340 ;
      RECT 174.390 241.880 180.230 242.340 ;
      RECT -0.150 242.340 46.490 243.440 ;
      RECT 51.990 242.340 61.850 243.440 ;
      RECT 67.350 242.340 77.210 243.440 ;
      RECT 82.710 242.340 92.570 243.440 ;
      RECT 98.070 242.340 138.170 243.440 ;
      RECT 143.670 242.340 153.530 243.440 ;
      RECT 159.030 242.340 168.890 243.440 ;
      RECT 174.390 242.340 184.250 243.440 ;
      RECT -0.150 243.440 189.270 244.960 ;
      RECT -0.150 244.960 0.000 246.960 ;
      RECT 189.120 244.960 189.270 246.960 ;
      RECT -0.150 246.960 189.270 248.480 ;
      RECT -0.150 248.480 46.490 249.580 ;
      RECT 51.990 248.480 61.850 249.580 ;
      RECT 67.350 248.480 77.210 249.580 ;
      RECT 82.710 248.480 92.570 249.580 ;
      RECT 98.070 248.480 138.170 249.580 ;
      RECT 143.670 248.480 153.530 249.580 ;
      RECT 159.030 248.480 168.890 249.580 ;
      RECT 174.390 248.480 184.250 249.580 ;
      RECT -0.150 249.580 42.470 250.040 ;
      RECT 51.990 249.580 57.830 250.040 ;
      RECT 67.350 249.580 73.190 250.040 ;
      RECT 82.710 249.580 88.550 250.040 ;
      RECT 98.070 249.580 134.150 250.040 ;
      RECT 143.670 249.580 149.510 250.040 ;
      RECT 159.030 249.580 164.870 250.040 ;
      RECT 174.390 249.580 180.230 250.040 ;
      RECT -0.150 250.040 42.470 251.140 ;
      RECT 51.990 250.040 57.830 251.140 ;
      RECT 67.350 250.040 73.190 251.140 ;
      RECT 82.710 250.040 88.550 251.140 ;
      RECT 98.070 250.040 134.150 251.140 ;
      RECT 143.670 250.040 149.510 251.140 ;
      RECT 159.030 250.040 164.870 251.140 ;
      RECT 174.390 250.040 180.230 251.140 ;
      RECT -0.150 251.140 189.270 267.320 ;
      RECT -0.150 267.320 0.000 269.320 ;
      RECT 189.120 267.320 189.270 269.320 ;
      RECT -0.150 269.320 189.270 285.750 ;
      RECT -0.150 285.750 37.690 286.850 ;
      RECT 42.460 285.750 189.270 286.850 ;
      RECT -0.150 286.850 37.690 287.010 ;
      RECT 42.460 286.850 189.270 287.010 ;
      RECT -0.150 287.010 37.690 288.110 ;
      RECT 40.215 287.010 189.270 288.110 ;
      RECT -0.150 288.110 189.270 289.680 ;
      RECT -0.150 289.680 0.000 291.680 ;
      RECT 176.560 289.680 189.270 291.680 ;
      RECT -0.150 291.680 189.270 312.040 ;
      RECT -0.150 312.040 0.000 313.040 ;
      RECT 176.560 312.040 189.270 313.040 ;
      RECT -0.150 313.040 189.270 314.040 ;
    LAYER Metal4 ;
      RECT 31.515 153.075 31.805 153.365 ;
      RECT 31.560 153.365 31.760 156.635 ;
      RECT 31.515 156.635 31.805 156.925 ;
      RECT 137.035 153.075 137.325 153.365 ;
      RECT 137.080 153.365 137.280 157.155 ;
      RECT 137.035 157.155 137.325 157.445 ;
      RECT 138.035 151.975 138.325 152.265 ;
      RECT 138.080 152.265 138.280 157.675 ;
      RECT 138.035 157.675 138.325 157.965 ;
      RECT 93.935 133.755 94.225 134.045 ;
      RECT 93.980 134.045 94.180 137.745 ;
      RECT 93.935 137.745 94.225 138.035 ;
      RECT 93.980 138.035 94.180 158.195 ;
      RECT 93.935 158.195 94.225 158.485 ;
      RECT 11.875 155.075 12.165 155.365 ;
      RECT 11.920 155.365 12.120 159.675 ;
      RECT 11.875 159.675 12.165 159.965 ;
      RECT 104.475 111.915 104.765 112.205 ;
      RECT 104.520 112.205 104.720 159.675 ;
      RECT 104.475 159.675 104.765 159.965 ;
      RECT 10.875 155.595 11.165 155.885 ;
      RECT 10.920 155.885 11.120 160.775 ;
      RECT 10.875 160.775 11.165 161.065 ;
      RECT 57.475 156.115 57.765 156.405 ;
      RECT 57.520 156.405 57.720 160.775 ;
      RECT 57.475 160.775 57.765 161.065 ;
      RECT 105.475 111.395 105.765 111.685 ;
      RECT 105.520 111.685 105.720 160.775 ;
      RECT 105.475 160.775 105.765 161.065 ;
      RECT 4.195 17.815 4.485 18.105 ;
      RECT 4.240 18.105 4.440 107.255 ;
      RECT 4.195 107.255 4.485 107.545 ;
      RECT 4.240 107.545 4.440 150.915 ;
      RECT 4.195 150.915 4.485 151.205 ;
      RECT 4.240 151.205 4.440 196.695 ;
      RECT 4.195 196.695 4.485 196.985 ;
      RECT 4.240 196.985 4.440 286.135 ;
      RECT 4.195 286.135 4.485 286.425 ;
      RECT 3.195 18.915 3.485 19.205 ;
      RECT 3.240 19.205 3.440 108.355 ;
      RECT 3.195 108.355 3.485 108.645 ;
      RECT 3.240 108.645 3.440 154.035 ;
      RECT 3.195 154.035 3.485 154.325 ;
      RECT 3.240 154.325 3.440 197.795 ;
      RECT 3.195 197.795 3.485 198.085 ;
      RECT 3.240 198.085 3.440 287.235 ;
      RECT 3.195 287.235 3.485 287.525 ;
      RECT 103.455 196.580 103.745 197.100 ;
      RECT 138.015 196.580 138.305 197.100 ;
      RECT 172.575 196.580 172.865 197.100 ;
      RECT 103.455 197.680 103.745 198.200 ;
      RECT 138.015 197.680 138.305 198.200 ;
      RECT 172.575 197.680 172.865 198.200 ;
      RECT 103.455 204.280 103.745 204.800 ;
      RECT 138.015 204.280 138.305 204.800 ;
      RECT 172.575 204.280 172.865 204.800 ;
      RECT 103.455 205.380 103.745 205.900 ;
      RECT 138.015 205.380 138.305 205.900 ;
      RECT 172.575 205.380 172.865 205.900 ;
      RECT 103.955 196.695 104.245 196.985 ;
      RECT 104.000 196.985 104.200 216.435 ;
      RECT 103.955 216.435 104.245 216.725 ;
      RECT 138.515 196.695 138.805 196.985 ;
      RECT 138.560 196.985 138.760 216.955 ;
      RECT 138.515 216.955 138.805 217.245 ;
      RECT 173.075 196.695 173.365 196.985 ;
      RECT 173.120 196.985 173.320 217.475 ;
      RECT 173.075 217.475 173.365 217.765 ;
      RECT 172.075 197.795 172.365 198.085 ;
      RECT 172.120 198.085 172.320 220.595 ;
      RECT 172.075 220.595 172.365 220.885 ;
      RECT 137.515 197.795 137.805 198.085 ;
      RECT 137.560 198.085 137.760 221.115 ;
      RECT 137.515 221.115 137.805 221.405 ;
      RECT 102.955 197.795 103.245 198.085 ;
      RECT 103.000 198.085 103.200 221.635 ;
      RECT 102.955 221.635 103.245 221.925 ;
      RECT 104.455 205.495 104.745 205.785 ;
      RECT 104.500 205.785 104.700 222.675 ;
      RECT 104.455 222.675 104.745 222.965 ;
      RECT 139.015 205.495 139.305 205.785 ;
      RECT 139.060 205.785 139.260 223.195 ;
      RECT 139.015 223.195 139.305 223.485 ;
      RECT 173.575 205.495 173.865 205.785 ;
      RECT 173.620 205.785 173.820 223.195 ;
      RECT 173.575 223.195 173.865 223.485 ;
      RECT 137.015 204.395 137.305 204.685 ;
      RECT 137.060 204.685 137.260 223.715 ;
      RECT 137.015 223.715 137.305 224.005 ;
      RECT 171.575 204.395 171.865 204.685 ;
      RECT 171.620 204.685 171.820 223.715 ;
      RECT 171.575 223.715 171.865 224.005 ;
      RECT 102.455 204.395 102.745 204.685 ;
      RECT 102.500 204.685 102.700 224.235 ;
      RECT 102.455 224.235 102.745 224.525 ;
      RECT 97.295 222.675 97.585 222.965 ;
      RECT 97.340 222.965 97.540 225.275 ;
      RECT 97.295 225.275 97.585 225.565 ;
      RECT 97.340 225.565 97.540 226.315 ;
      RECT 97.295 226.315 97.585 226.605 ;
      RECT 109.815 202.915 110.105 203.205 ;
      RECT 109.860 203.205 110.060 227.415 ;
      RECT 109.815 227.415 110.105 227.705 ;
      RECT 108.815 227.300 109.105 227.820 ;
      RECT 107.815 207.075 108.105 207.365 ;
      RECT 107.860 207.365 108.060 228.515 ;
      RECT 107.815 228.515 108.105 228.805 ;
      RECT 108.815 228.400 109.105 228.920 ;
      RECT 130.955 223.195 131.245 223.485 ;
      RECT 131.000 223.485 131.200 241.415 ;
      RECT 130.955 241.415 131.245 241.705 ;
      RECT 145.815 222.675 146.105 222.965 ;
      RECT 145.860 222.965 146.060 241.415 ;
      RECT 145.815 241.415 146.105 241.705 ;
      RECT 161.175 223.195 161.465 223.485 ;
      RECT 161.220 223.485 161.420 241.415 ;
      RECT 161.175 241.415 161.465 241.705 ;
      RECT 176.535 223.195 176.825 223.485 ;
      RECT 176.580 223.485 176.780 241.415 ;
      RECT 176.535 241.415 176.825 241.705 ;
      RECT 108.815 241.300 109.105 241.820 ;
      RECT 129.455 241.300 129.745 241.820 ;
      RECT 144.815 241.300 145.105 241.820 ;
      RECT 160.175 241.300 160.465 241.820 ;
      RECT 175.535 241.300 175.825 241.820 ;
      RECT 130.455 223.715 130.745 224.005 ;
      RECT 130.500 224.005 130.700 242.515 ;
      RECT 130.455 242.515 130.745 242.805 ;
      RECT 143.815 224.235 144.105 224.525 ;
      RECT 143.860 224.525 144.060 242.515 ;
      RECT 143.815 242.515 144.105 242.805 ;
      RECT 159.175 223.715 159.465 224.005 ;
      RECT 159.220 224.005 159.420 242.515 ;
      RECT 159.175 242.515 159.465 242.805 ;
      RECT 174.535 223.715 174.825 224.005 ;
      RECT 174.580 224.005 174.780 242.515 ;
      RECT 174.535 242.515 174.825 242.805 ;
      RECT 108.815 242.400 109.105 242.920 ;
      RECT 129.455 242.400 129.745 242.920 ;
      RECT 144.815 242.400 145.105 242.920 ;
      RECT 160.175 242.400 160.465 242.920 ;
      RECT 175.535 242.400 175.825 242.920 ;
      RECT 108.315 203.435 108.605 203.725 ;
      RECT 108.360 203.725 108.560 242.515 ;
      RECT 108.315 242.515 108.605 242.805 ;
      RECT 108.360 242.805 108.560 249.115 ;
      RECT 108.315 249.115 108.605 249.405 ;
      RECT 108.815 249.000 109.105 249.520 ;
      RECT 129.455 249.000 129.745 249.520 ;
      RECT 144.815 249.000 145.105 249.520 ;
      RECT 160.175 249.000 160.465 249.520 ;
      RECT 175.535 249.000 175.825 249.520 ;
      RECT 109.315 206.555 109.605 206.845 ;
      RECT 109.360 206.845 109.560 241.415 ;
      RECT 109.315 241.415 109.605 241.705 ;
      RECT 109.360 241.705 109.560 250.215 ;
      RECT 109.315 250.215 109.605 250.505 ;
      RECT 108.815 250.100 109.105 250.620 ;
      RECT 129.455 250.100 129.745 250.620 ;
      RECT 144.815 250.100 145.105 250.620 ;
      RECT 160.175 250.100 160.465 250.620 ;
      RECT 175.535 250.100 175.825 250.620 ;
      RECT 108.815 263.000 109.105 263.520 ;
      RECT 108.815 264.100 109.105 264.620 ;
      RECT 97.295 262.195 97.585 262.485 ;
      RECT 97.340 262.485 97.540 265.315 ;
      RECT 97.295 265.315 97.585 265.605 ;
      RECT 188.675 225.275 188.965 225.565 ;
      RECT 188.720 225.565 188.920 226.315 ;
      RECT 188.675 226.315 188.965 226.605 ;
      RECT 188.720 226.605 188.920 262.195 ;
      RECT 188.675 262.195 188.965 262.485 ;
      RECT 188.720 262.485 188.920 265.315 ;
      RECT 188.675 265.315 188.965 265.605 ;
      RECT 108.315 263.115 108.605 263.405 ;
      RECT 108.360 263.405 108.560 266.355 ;
      RECT 108.315 266.355 108.605 266.645 ;
      RECT 129.955 250.215 130.245 250.505 ;
      RECT 130.000 250.505 130.200 269.995 ;
      RECT 129.955 269.995 130.245 270.285 ;
      RECT 144.315 249.115 144.605 249.405 ;
      RECT 144.360 249.405 144.560 270.515 ;
      RECT 144.315 270.515 144.605 270.805 ;
      RECT 128.955 249.115 129.245 249.405 ;
      RECT 129.000 249.405 129.200 271.035 ;
      RECT 128.955 271.035 129.245 271.325 ;
      RECT 159.675 249.115 159.965 249.405 ;
      RECT 159.720 249.405 159.920 271.035 ;
      RECT 159.675 271.035 159.965 271.325 ;
      RECT 175.035 249.115 175.325 249.405 ;
      RECT 175.080 249.405 175.280 271.035 ;
      RECT 175.035 271.035 175.325 271.325 ;
      RECT 109.315 264.215 109.605 264.505 ;
      RECT 109.360 264.505 109.560 274.155 ;
      RECT 109.315 274.155 109.605 274.445 ;
      RECT 160.675 250.215 160.965 250.505 ;
      RECT 160.720 250.505 160.920 274.155 ;
      RECT 160.675 274.155 160.965 274.445 ;
      RECT 176.035 250.215 176.325 250.505 ;
      RECT 176.080 250.505 176.280 274.155 ;
      RECT 176.035 274.155 176.325 274.445 ;
      RECT 145.315 250.215 145.605 250.505 ;
      RECT 145.360 250.505 145.560 274.675 ;
      RECT 145.315 274.675 145.605 274.965 ;
      RECT 104.975 159.560 105.265 160.080 ;
      RECT 104.455 269.475 104.745 269.765 ;
      RECT 104.500 269.765 104.700 286.135 ;
      RECT 104.455 286.135 104.745 286.425 ;
      RECT 139.015 268.955 139.305 269.245 ;
      RECT 139.060 269.245 139.260 286.135 ;
      RECT 139.015 286.135 139.305 286.425 ;
      RECT 173.575 268.435 173.865 268.725 ;
      RECT 173.620 268.725 173.820 286.135 ;
      RECT 173.575 286.135 173.865 286.425 ;
      RECT 103.455 286.020 103.745 286.540 ;
      RECT 138.015 286.020 138.305 286.540 ;
      RECT 172.575 286.020 172.865 286.540 ;
      RECT 104.975 160.660 105.265 161.180 ;
      RECT 102.455 266.875 102.745 267.165 ;
      RECT 102.500 267.165 102.700 287.235 ;
      RECT 102.455 287.235 102.745 287.525 ;
      RECT 137.015 267.395 137.305 267.685 ;
      RECT 137.060 267.685 137.260 287.235 ;
      RECT 137.015 287.235 137.305 287.525 ;
      RECT 171.575 267.915 171.865 268.205 ;
      RECT 171.620 268.205 171.820 287.235 ;
      RECT 171.575 287.235 171.865 287.525 ;
      RECT 103.455 287.120 103.745 287.640 ;
      RECT 138.015 287.120 138.305 287.640 ;
      RECT 172.575 287.120 172.865 287.640 ;
      RECT 102.955 270.515 103.245 270.805 ;
      RECT 103.000 270.805 103.200 293.835 ;
      RECT 102.955 293.835 103.245 294.125 ;
      RECT 137.515 271.035 137.805 271.325 ;
      RECT 137.560 271.325 137.760 293.835 ;
      RECT 137.515 293.835 137.805 294.125 ;
      RECT 172.075 271.035 172.365 271.325 ;
      RECT 172.120 271.325 172.320 293.835 ;
      RECT 172.075 293.835 172.365 294.125 ;
      RECT 103.455 293.720 103.745 294.240 ;
      RECT 138.015 293.720 138.305 294.240 ;
      RECT 172.575 293.720 172.865 294.240 ;
      RECT 103.955 274.675 104.245 274.965 ;
      RECT 104.000 274.965 104.200 294.935 ;
      RECT 103.955 294.935 104.245 295.225 ;
      RECT 138.515 274.155 138.805 274.445 ;
      RECT 138.560 274.445 138.760 294.935 ;
      RECT 138.515 294.935 138.805 295.225 ;
      RECT 173.075 274.155 173.365 274.445 ;
      RECT 173.120 274.445 173.320 294.935 ;
      RECT 173.075 294.935 173.365 295.225 ;
      RECT 103.455 294.820 103.745 295.340 ;
      RECT 138.015 294.820 138.305 295.340 ;
      RECT 172.575 294.820 172.865 295.340 ;
      RECT 16.635 181.595 16.925 181.885 ;
      RECT 16.680 181.885 16.880 242.515 ;
      RECT 16.635 242.515 16.925 242.805 ;
      RECT 16.680 242.805 16.880 249.115 ;
      RECT 16.635 249.115 16.925 249.405 ;
      RECT 17.635 181.075 17.925 181.365 ;
      RECT 17.680 181.365 17.880 241.415 ;
      RECT 17.635 241.415 17.925 241.705 ;
      RECT 17.680 241.705 17.880 250.215 ;
      RECT 17.635 250.215 17.925 250.505 ;
      RECT 38.275 215.915 38.565 216.205 ;
      RECT 38.320 216.205 38.520 241.415 ;
      RECT 38.275 241.415 38.565 241.705 ;
      RECT 53.635 216.435 53.925 216.725 ;
      RECT 53.680 216.725 53.880 241.415 ;
      RECT 53.635 241.415 53.925 241.705 ;
      RECT 68.995 216.955 69.285 217.245 ;
      RECT 69.040 217.245 69.240 241.415 ;
      RECT 68.995 241.415 69.285 241.705 ;
      RECT 84.355 217.475 84.645 217.765 ;
      RECT 84.400 217.765 84.600 241.415 ;
      RECT 84.355 241.415 84.645 241.705 ;
      RECT 37.275 220.595 37.565 220.885 ;
      RECT 37.320 220.885 37.520 242.515 ;
      RECT 37.275 242.515 37.565 242.805 ;
      RECT 52.635 221.635 52.925 221.925 ;
      RECT 52.680 221.925 52.880 242.515 ;
      RECT 52.635 242.515 52.925 242.805 ;
      RECT 67.995 221.115 68.285 221.405 ;
      RECT 68.040 221.405 68.240 242.515 ;
      RECT 67.995 242.515 68.285 242.805 ;
      RECT 83.355 220.595 83.645 220.885 ;
      RECT 83.400 220.885 83.600 242.515 ;
      RECT 83.355 242.515 83.645 242.805 ;
      RECT 83.855 250.100 84.145 250.620 ;
      RECT 52.135 249.115 52.425 249.405 ;
      RECT 52.180 249.405 52.380 266.875 ;
      RECT 52.135 266.875 52.425 267.165 ;
      RECT 67.495 249.115 67.785 249.405 ;
      RECT 67.540 249.405 67.740 267.395 ;
      RECT 67.495 267.395 67.785 267.685 ;
      RECT 82.855 249.115 83.145 249.405 ;
      RECT 82.900 249.405 83.100 267.915 ;
      RECT 82.855 267.915 83.145 268.205 ;
      RECT 84.855 250.215 85.145 250.505 ;
      RECT 84.900 250.505 85.100 268.435 ;
      RECT 84.855 268.435 85.145 268.725 ;
      RECT 69.495 250.215 69.785 250.505 ;
      RECT 69.540 250.505 69.740 268.955 ;
      RECT 69.495 268.955 69.785 269.245 ;
      RECT 54.135 250.215 54.425 250.505 ;
      RECT 54.180 250.505 54.380 269.475 ;
      RECT 54.135 269.475 54.425 269.765 ;
      RECT 69.895 270.515 70.185 270.805 ;
      RECT 69.940 270.805 70.140 286.135 ;
      RECT 69.895 286.135 70.185 286.425 ;
      RECT 68.895 286.020 69.185 286.540 ;
      RECT 83.855 242.400 84.145 242.920 ;
      RECT 53.135 242.400 53.425 242.920 ;
      RECT 53.135 249.000 53.425 249.520 ;
      RECT 68.495 249.000 68.785 249.520 ;
      RECT 67.895 267.915 68.185 268.205 ;
      RECT 67.940 268.205 68.140 287.235 ;
      RECT 67.895 287.235 68.185 287.525 ;
      RECT 68.895 287.120 69.185 287.640 ;
      RECT 68.395 271.035 68.685 271.325 ;
      RECT 68.440 271.325 68.640 293.835 ;
      RECT 68.395 293.835 68.685 294.125 ;
      RECT 53.135 241.300 53.425 241.820 ;
      RECT 68.495 241.300 68.785 241.820 ;
      RECT 83.855 241.300 84.145 241.820 ;
      RECT 68.895 293.720 69.185 294.240 ;
      RECT 69.395 269.995 69.685 270.285 ;
      RECT 69.440 270.285 69.640 294.935 ;
      RECT 69.395 294.935 69.685 295.225 ;
      RECT 83.855 249.000 84.145 249.520 ;
      RECT 68.895 294.820 69.185 295.340 ;
      RECT 68.495 242.400 68.785 242.920 ;
      RECT 53.135 250.100 53.425 250.620 ;
      RECT 68.495 250.100 68.785 250.620 ;
      RECT 17.135 250.100 17.425 250.620 ;
      RECT 36.775 249.115 37.065 249.405 ;
      RECT 36.820 249.405 37.020 267.915 ;
      RECT 36.775 267.915 37.065 268.205 ;
      RECT 37.775 250.100 38.065 250.620 ;
      RECT 17.135 242.400 17.425 242.920 ;
      RECT 3.695 287.120 3.985 287.640 ;
      RECT 37.775 242.400 38.065 242.920 ;
      RECT 17.135 241.300 17.425 241.820 ;
      RECT 37.775 241.300 38.065 241.820 ;
      RECT 17.635 264.215 17.925 264.505 ;
      RECT 17.680 264.505 17.880 288.195 ;
      RECT 17.635 288.195 17.925 288.485 ;
      RECT 17.135 249.000 17.425 249.520 ;
      RECT 38.775 250.215 39.065 250.505 ;
      RECT 38.820 250.505 39.020 270.515 ;
      RECT 38.775 270.515 39.065 270.805 ;
      RECT 36.255 272.020 36.545 272.540 ;
      RECT 35.755 266.355 36.045 266.645 ;
      RECT 35.800 266.645 36.000 273.235 ;
      RECT 35.755 273.235 36.045 273.525 ;
      RECT 36.255 273.120 36.545 273.640 ;
      RECT 36.755 272.135 37.045 272.425 ;
      RECT 36.800 272.425 37.000 274.155 ;
      RECT 36.755 274.155 37.045 274.445 ;
      RECT 16.635 263.115 16.925 263.405 ;
      RECT 16.680 263.405 16.880 285.075 ;
      RECT 16.635 285.075 16.925 285.365 ;
      RECT 17.135 263.000 17.425 263.520 ;
      RECT 3.695 286.020 3.985 286.540 ;
      RECT 17.135 264.100 17.425 264.620 ;
      RECT 37.775 249.000 38.065 249.520 ;
      RECT 35.755 285.075 36.045 285.365 ;
      RECT 35.800 285.365 36.000 307.835 ;
      RECT 35.755 307.835 36.045 308.125 ;
      RECT 36.255 307.720 36.545 308.240 ;
      RECT 36.755 288.195 37.045 288.485 ;
      RECT 36.800 288.485 37.000 308.935 ;
      RECT 36.755 308.935 37.045 309.225 ;
      RECT 36.255 308.820 36.545 309.340 ;
      RECT 23.375 262.195 23.665 262.485 ;
      RECT 23.420 262.485 23.620 271.905 ;
      RECT 23.375 271.905 23.665 272.195 ;
      RECT 23.420 272.195 23.620 309.165 ;
      RECT 23.375 309.165 23.665 309.455 ;
      RECT 35.255 183.795 35.545 184.085 ;
      RECT 35.300 184.085 35.500 207.075 ;
      RECT 35.255 207.075 35.545 207.365 ;
      RECT 20.035 157.675 20.325 157.965 ;
      RECT 20.080 157.965 20.280 160.775 ;
      RECT 20.035 160.775 20.325 161.065 ;
      RECT 3.695 197.680 3.985 198.200 ;
      RECT 19.535 160.660 19.825 161.180 ;
      RECT 36.255 182.580 36.545 183.100 ;
      RECT 36.255 183.680 36.545 184.200 ;
      RECT 23.375 158.195 23.665 158.485 ;
      RECT 23.420 158.485 23.620 182.465 ;
      RECT 23.375 182.465 23.665 182.755 ;
      RECT 23.420 182.755 23.620 219.725 ;
      RECT 23.375 219.725 23.665 220.015 ;
      RECT 23.420 220.015 23.620 222.675 ;
      RECT 23.375 222.675 23.665 222.965 ;
      RECT 32.015 160.660 32.305 161.180 ;
      RECT 11.375 159.560 11.665 160.080 ;
      RECT 36.255 218.280 36.545 218.800 ;
      RECT 18.135 217.475 18.425 217.765 ;
      RECT 18.180 217.765 18.380 227.415 ;
      RECT 18.135 227.415 18.425 227.705 ;
      RECT 3.695 196.580 3.985 197.100 ;
      RECT 17.135 227.300 17.425 227.820 ;
      RECT 37.255 182.695 37.545 182.985 ;
      RECT 37.300 182.985 37.500 202.915 ;
      RECT 37.255 202.915 37.545 203.205 ;
      RECT 32.515 160.775 32.805 161.065 ;
      RECT 32.560 161.065 32.760 161.835 ;
      RECT 32.515 161.835 32.805 162.125 ;
      RECT 16.135 223.715 16.425 224.005 ;
      RECT 16.180 224.005 16.380 228.515 ;
      RECT 16.135 228.515 16.425 228.805 ;
      RECT 35.255 218.395 35.545 218.685 ;
      RECT 35.300 218.685 35.500 223.715 ;
      RECT 35.255 223.715 35.545 224.005 ;
      RECT 19.535 159.560 19.825 160.080 ;
      RECT 17.135 228.400 17.425 228.920 ;
      RECT 32.015 159.560 32.305 160.080 ;
      RECT 37.255 217.475 37.545 217.765 ;
      RECT 37.300 217.765 37.500 219.495 ;
      RECT 37.255 219.495 37.545 219.785 ;
      RECT 31.515 158.715 31.805 159.005 ;
      RECT 31.560 159.005 31.760 159.675 ;
      RECT 31.515 159.675 31.805 159.965 ;
      RECT 36.255 219.380 36.545 219.900 ;
      RECT 19.035 157.155 19.325 157.445 ;
      RECT 19.080 157.445 19.280 159.675 ;
      RECT 19.035 159.675 19.325 159.965 ;
      RECT 11.375 160.660 11.665 161.180 ;
      RECT 55.055 160.660 55.345 161.180 ;
      RECT 69.895 204.395 70.185 204.685 ;
      RECT 69.940 204.685 70.140 223.715 ;
      RECT 69.895 223.715 70.185 224.005 ;
      RECT 81.435 158.715 81.725 159.005 ;
      RECT 81.480 159.005 81.680 159.675 ;
      RECT 81.435 159.675 81.725 159.965 ;
      RECT 80.515 160.775 80.805 161.065 ;
      RECT 80.560 161.065 80.760 181.075 ;
      RECT 80.515 181.075 80.805 181.365 ;
      RECT 79.515 159.675 79.805 159.965 ;
      RECT 79.560 159.965 79.760 181.595 ;
      RECT 79.515 181.595 79.805 181.885 ;
      RECT 70.395 205.495 70.685 205.785 ;
      RECT 70.440 205.785 70.640 223.195 ;
      RECT 70.395 223.195 70.685 223.485 ;
      RECT 68.895 205.380 69.185 205.900 ;
      RECT 80.015 159.560 80.305 160.080 ;
      RECT 81.935 159.560 82.225 160.080 ;
      RECT 82.435 160.775 82.725 161.065 ;
      RECT 82.480 161.065 82.680 161.835 ;
      RECT 82.435 161.835 82.725 162.125 ;
      RECT 69.395 196.695 69.685 196.985 ;
      RECT 69.440 196.985 69.640 215.915 ;
      RECT 69.395 215.915 69.685 216.205 ;
      RECT 54.555 159.675 54.845 159.965 ;
      RECT 54.600 159.965 54.800 203.435 ;
      RECT 54.555 203.435 54.845 203.725 ;
      RECT 68.895 204.280 69.185 204.800 ;
      RECT 68.395 197.795 68.685 198.085 ;
      RECT 68.440 198.085 68.640 220.595 ;
      RECT 68.395 220.595 68.685 220.885 ;
      RECT 56.975 160.660 57.265 161.180 ;
      RECT 80.015 160.660 80.305 161.180 ;
      RECT 55.055 159.560 55.345 160.080 ;
      RECT 81.935 160.660 82.225 161.180 ;
      RECT 68.895 197.680 69.185 198.200 ;
      RECT 56.475 156.635 56.765 156.925 ;
      RECT 56.520 156.925 56.720 159.675 ;
      RECT 56.475 159.675 56.765 159.965 ;
      RECT 68.895 196.580 69.185 197.100 ;
      RECT 56.975 159.560 57.265 160.080 ;
      RECT 55.555 160.775 55.845 161.065 ;
      RECT 55.600 161.065 55.800 206.555 ;
      RECT 55.555 206.555 55.845 206.845 ;
      RECT 52.135 70.235 52.425 70.525 ;
      RECT 52.180 70.525 52.380 87.995 ;
      RECT 52.135 87.995 52.425 88.285 ;
      RECT 67.495 70.235 67.785 70.525 ;
      RECT 67.540 70.525 67.740 88.515 ;
      RECT 67.495 88.515 67.785 88.805 ;
      RECT 36.775 70.235 37.065 70.525 ;
      RECT 36.820 70.525 37.020 89.035 ;
      RECT 36.775 89.035 37.065 89.325 ;
      RECT 82.855 70.235 83.145 70.525 ;
      RECT 82.900 70.525 83.100 89.035 ;
      RECT 82.855 89.035 83.145 89.325 ;
      RECT 84.855 71.335 85.145 71.625 ;
      RECT 84.900 71.625 85.100 89.555 ;
      RECT 84.855 89.555 85.145 89.845 ;
      RECT 69.495 71.335 69.785 71.625 ;
      RECT 69.540 71.625 69.740 90.075 ;
      RECT 69.495 90.075 69.785 90.365 ;
      RECT 54.135 71.335 54.425 71.625 ;
      RECT 54.180 71.625 54.380 90.595 ;
      RECT 54.135 90.595 54.425 90.885 ;
      RECT 38.775 71.335 39.065 71.625 ;
      RECT 38.820 71.625 39.020 91.635 ;
      RECT 38.775 91.635 39.065 91.925 ;
      RECT 17.635 62.535 17.925 62.825 ;
      RECT 17.680 62.825 17.880 71.335 ;
      RECT 17.635 71.335 17.925 71.625 ;
      RECT 17.680 71.625 17.880 106.195 ;
      RECT 17.635 106.195 17.925 106.485 ;
      RECT 16.635 63.635 16.925 63.925 ;
      RECT 16.680 63.925 16.880 70.235 ;
      RECT 16.635 70.235 16.925 70.525 ;
      RECT 16.680 70.525 16.880 109.315 ;
      RECT 16.635 109.315 16.925 109.605 ;
      RECT 68.895 107.140 69.185 107.660 ;
      RECT 67.895 89.035 68.185 89.325 ;
      RECT 67.940 89.325 68.140 108.355 ;
      RECT 67.895 108.355 68.185 108.645 ;
      RECT 68.895 108.240 69.185 108.760 ;
      RECT 69.895 91.635 70.185 91.925 ;
      RECT 69.940 91.925 70.140 107.255 ;
      RECT 69.895 107.255 70.185 107.545 ;
      RECT 68.395 92.155 68.685 92.445 ;
      RECT 68.440 92.445 68.640 114.955 ;
      RECT 68.395 114.955 68.685 115.245 ;
      RECT 68.895 114.840 69.185 115.360 ;
      RECT 69.395 91.115 69.685 91.405 ;
      RECT 69.440 91.405 69.640 116.055 ;
      RECT 69.395 116.055 69.685 116.345 ;
      RECT 68.895 115.940 69.185 116.460 ;
      RECT 55.555 106.195 55.845 106.485 ;
      RECT 55.600 106.485 55.800 151.975 ;
      RECT 55.555 151.975 55.845 152.265 ;
      RECT 74.755 150.915 75.045 151.205 ;
      RECT 74.800 151.205 75.000 151.975 ;
      RECT 74.755 151.975 75.045 152.265 ;
      RECT 55.055 151.860 55.345 152.380 ;
      RECT 74.255 151.860 74.545 152.380 ;
      RECT 54.555 109.315 54.845 109.605 ;
      RECT 54.600 109.605 54.800 153.075 ;
      RECT 54.555 153.075 54.845 153.365 ;
      RECT 55.055 152.960 55.345 153.480 ;
      RECT 74.255 152.960 74.545 153.480 ;
      RECT 73.755 153.075 74.045 153.365 ;
      RECT 73.800 153.365 74.000 154.035 ;
      RECT 73.755 154.035 74.045 154.325 ;
      RECT 17.135 85.220 17.425 85.740 ;
      RECT 3.695 107.140 3.985 107.660 ;
      RECT 35.255 105.675 35.545 105.965 ;
      RECT 35.300 105.965 35.500 128.955 ;
      RECT 35.255 128.955 35.545 129.245 ;
      RECT 36.255 128.840 36.545 129.360 ;
      RECT 37.255 109.835 37.545 110.125 ;
      RECT 37.300 110.125 37.500 130.055 ;
      RECT 37.255 130.055 37.545 130.345 ;
      RECT 36.255 129.940 36.545 130.460 ;
      RECT 23.375 82.795 23.665 83.085 ;
      RECT 23.420 83.085 23.620 93.025 ;
      RECT 23.375 93.025 23.665 93.315 ;
      RECT 23.420 93.315 23.620 130.285 ;
      RECT 23.375 130.285 23.665 130.575 ;
      RECT 23.420 130.575 23.620 133.755 ;
      RECT 23.375 133.755 23.665 134.045 ;
      RECT 11.875 150.395 12.165 150.685 ;
      RECT 11.920 150.685 12.120 151.975 ;
      RECT 11.875 151.975 12.165 152.265 ;
      RECT 20.035 149.355 20.325 149.645 ;
      RECT 20.080 149.645 20.280 151.975 ;
      RECT 20.035 151.975 20.325 152.265 ;
      RECT 37.255 83.315 37.545 83.605 ;
      RECT 37.300 83.605 37.500 93.255 ;
      RECT 37.255 93.255 37.545 93.545 ;
      RECT 36.255 93.140 36.545 93.660 ;
      RECT 11.375 151.860 11.665 152.380 ;
      RECT 19.535 151.860 19.825 152.380 ;
      RECT 32.015 151.860 32.305 152.380 ;
      RECT 3.695 108.240 3.985 108.760 ;
      RECT 35.255 87.475 35.545 87.765 ;
      RECT 35.300 87.765 35.500 94.355 ;
      RECT 35.255 94.355 35.545 94.645 ;
      RECT 19.035 149.875 19.325 150.165 ;
      RECT 19.080 150.165 19.280 153.075 ;
      RECT 19.035 153.075 19.325 153.365 ;
      RECT 36.255 94.240 36.545 94.760 ;
      RECT 11.375 152.960 11.665 153.480 ;
      RECT 19.535 152.960 19.825 153.480 ;
      RECT 32.015 152.960 32.305 153.480 ;
      RECT 18.135 85.335 18.425 85.625 ;
      RECT 18.180 85.625 18.380 109.835 ;
      RECT 18.135 109.835 18.425 110.125 ;
      RECT 16.135 84.235 16.425 84.525 ;
      RECT 16.180 84.525 16.380 105.675 ;
      RECT 16.135 105.675 16.425 105.965 ;
      RECT 17.135 84.120 17.425 84.640 ;
      RECT 10.875 153.075 11.165 153.365 ;
      RECT 10.920 153.365 11.120 154.555 ;
      RECT 10.875 154.555 11.165 154.845 ;
      RECT 32.515 151.975 32.805 152.265 ;
      RECT 32.560 152.265 32.760 156.115 ;
      RECT 32.515 156.115 32.805 156.405 ;
      RECT 35.755 39.515 36.045 39.805 ;
      RECT 35.800 39.805 36.000 44.315 ;
      RECT 35.755 44.315 36.045 44.605 ;
      RECT 36.755 40.615 37.045 40.905 ;
      RECT 36.800 40.905 37.000 44.835 ;
      RECT 36.755 44.835 37.045 45.125 ;
      RECT 17.635 44.835 17.925 45.125 ;
      RECT 17.680 45.125 17.880 48.535 ;
      RECT 17.635 48.535 17.925 48.825 ;
      RECT 17.135 48.420 17.425 48.940 ;
      RECT 16.635 44.315 16.925 44.605 ;
      RECT 16.680 44.605 16.880 49.635 ;
      RECT 16.635 49.635 16.925 49.925 ;
      RECT 17.135 49.520 17.425 50.040 ;
      RECT 38.275 37.035 38.565 37.325 ;
      RECT 38.320 37.325 38.520 62.535 ;
      RECT 38.275 62.535 38.565 62.825 ;
      RECT 17.135 62.420 17.425 62.940 ;
      RECT 37.775 62.420 38.065 62.940 ;
      RECT 37.275 41.715 37.565 42.005 ;
      RECT 37.320 42.005 37.520 63.635 ;
      RECT 37.275 63.635 37.565 63.925 ;
      RECT 17.135 63.520 17.425 64.040 ;
      RECT 37.775 63.520 38.065 64.040 ;
      RECT 17.135 70.120 17.425 70.640 ;
      RECT 37.775 70.120 38.065 70.640 ;
      RECT 17.135 71.220 17.425 71.740 ;
      RECT 37.775 71.220 38.065 71.740 ;
      RECT 23.375 3.585 23.665 3.875 ;
      RECT 23.420 3.875 23.620 40.845 ;
      RECT 23.375 40.845 23.665 41.135 ;
      RECT 23.420 41.135 23.620 43.795 ;
      RECT 23.375 43.795 23.665 44.085 ;
      RECT 36.255 3.700 36.545 4.220 ;
      RECT 36.255 4.800 36.545 5.320 ;
      RECT 3.695 17.700 3.985 18.220 ;
      RECT 3.695 18.800 3.985 19.320 ;
      RECT 36.755 3.815 37.045 4.105 ;
      RECT 36.800 4.105 37.000 24.555 ;
      RECT 36.755 24.555 37.045 24.845 ;
      RECT 35.755 4.915 36.045 5.205 ;
      RECT 35.800 5.205 36.000 27.675 ;
      RECT 35.755 27.675 36.045 27.965 ;
      RECT 36.255 39.400 36.545 39.920 ;
      RECT 36.255 40.500 36.545 41.020 ;
      RECT 53.135 71.220 53.425 71.740 ;
      RECT 68.495 71.220 68.785 71.740 ;
      RECT 83.855 71.220 84.145 71.740 ;
      RECT 68.495 62.420 68.785 62.940 ;
      RECT 83.855 62.420 84.145 62.940 ;
      RECT 68.395 18.915 68.685 19.205 ;
      RECT 68.440 19.205 68.640 41.715 ;
      RECT 68.395 41.715 68.685 42.005 ;
      RECT 52.635 42.755 52.925 43.045 ;
      RECT 52.680 43.045 52.880 63.635 ;
      RECT 52.635 63.635 52.925 63.925 ;
      RECT 67.995 42.235 68.285 42.525 ;
      RECT 68.040 42.525 68.240 63.635 ;
      RECT 67.995 63.635 68.285 63.925 ;
      RECT 83.355 41.715 83.645 42.005 ;
      RECT 83.400 42.005 83.600 63.635 ;
      RECT 83.355 63.635 83.645 63.925 ;
      RECT 53.635 37.555 53.925 37.845 ;
      RECT 53.680 37.845 53.880 62.535 ;
      RECT 53.635 62.535 53.925 62.825 ;
      RECT 68.995 38.075 69.285 38.365 ;
      RECT 69.040 38.365 69.240 62.535 ;
      RECT 68.995 62.535 69.285 62.825 ;
      RECT 53.135 63.520 53.425 64.040 ;
      RECT 68.495 63.520 68.785 64.040 ;
      RECT 83.855 63.520 84.145 64.040 ;
      RECT 84.355 38.595 84.645 38.885 ;
      RECT 84.400 38.885 84.600 62.535 ;
      RECT 84.355 62.535 84.645 62.825 ;
      RECT 70.395 26.615 70.685 26.905 ;
      RECT 70.440 26.905 70.640 44.835 ;
      RECT 70.395 44.835 70.685 45.125 ;
      RECT 68.895 17.700 69.185 18.220 ;
      RECT 53.135 70.120 53.425 70.640 ;
      RECT 68.895 18.800 69.185 19.320 ;
      RECT 68.495 70.120 68.785 70.640 ;
      RECT 68.895 25.400 69.185 25.920 ;
      RECT 68.895 26.500 69.185 27.020 ;
      RECT 83.855 70.120 84.145 70.640 ;
      RECT 69.395 17.815 69.685 18.105 ;
      RECT 69.440 18.105 69.640 37.035 ;
      RECT 69.395 37.035 69.685 37.325 ;
      RECT 69.895 25.515 70.185 25.805 ;
      RECT 69.940 25.805 70.140 44.315 ;
      RECT 69.895 44.315 70.185 44.605 ;
      RECT 53.135 62.420 53.425 62.940 ;
      RECT 188.675 46.395 188.965 46.685 ;
      RECT 188.720 46.685 188.920 47.435 ;
      RECT 188.675 47.435 188.965 47.725 ;
      RECT 188.720 47.725 188.920 82.795 ;
      RECT 188.675 82.795 188.965 83.085 ;
      RECT 188.720 83.085 188.920 86.435 ;
      RECT 188.675 86.435 188.965 86.725 ;
      RECT 129.955 71.335 130.245 71.625 ;
      RECT 130.000 71.625 130.200 91.115 ;
      RECT 129.955 91.115 130.245 91.405 ;
      RECT 144.315 70.235 144.605 70.525 ;
      RECT 144.360 70.525 144.560 91.635 ;
      RECT 144.315 91.635 144.605 91.925 ;
      RECT 128.955 70.235 129.245 70.525 ;
      RECT 129.000 70.525 129.200 92.155 ;
      RECT 128.955 92.155 129.245 92.445 ;
      RECT 159.675 70.235 159.965 70.525 ;
      RECT 159.720 70.525 159.920 92.155 ;
      RECT 159.675 92.155 159.965 92.445 ;
      RECT 175.035 70.235 175.325 70.525 ;
      RECT 175.080 70.525 175.280 92.155 ;
      RECT 175.035 92.155 175.325 92.445 ;
      RECT 160.675 71.335 160.965 71.625 ;
      RECT 160.720 71.625 160.920 95.275 ;
      RECT 160.675 95.275 160.965 95.565 ;
      RECT 176.035 71.335 176.325 71.625 ;
      RECT 176.080 71.625 176.280 95.275 ;
      RECT 176.035 95.275 176.325 95.565 ;
      RECT 145.315 71.335 145.605 71.625 ;
      RECT 145.360 71.625 145.560 95.795 ;
      RECT 145.315 95.795 145.605 96.085 ;
      RECT 109.315 62.535 109.605 62.825 ;
      RECT 109.360 62.825 109.560 71.335 ;
      RECT 109.315 71.335 109.605 71.625 ;
      RECT 109.360 71.625 109.560 111.395 ;
      RECT 109.315 111.395 109.605 111.685 ;
      RECT 108.315 63.635 108.605 63.925 ;
      RECT 108.360 63.925 108.560 70.235 ;
      RECT 108.315 70.235 108.605 70.525 ;
      RECT 108.360 70.525 108.560 111.915 ;
      RECT 108.315 111.915 108.605 112.205 ;
      RECT 168.255 152.960 168.545 153.480 ;
      RECT 152.395 151.975 152.685 152.265 ;
      RECT 152.440 152.265 152.640 154.555 ;
      RECT 152.395 154.555 152.685 154.845 ;
      RECT 168.755 151.975 169.045 152.265 ;
      RECT 168.800 152.265 169.000 155.075 ;
      RECT 168.755 155.075 169.045 155.365 ;
      RECT 173.575 89.555 173.865 89.845 ;
      RECT 173.620 89.845 173.820 107.255 ;
      RECT 173.575 107.255 173.865 107.545 ;
      RECT 172.575 107.140 172.865 107.660 ;
      RECT 171.575 89.035 171.865 89.325 ;
      RECT 171.620 89.325 171.820 108.355 ;
      RECT 171.575 108.355 171.865 108.645 ;
      RECT 172.575 108.240 172.865 108.760 ;
      RECT 167.755 153.075 168.045 153.365 ;
      RECT 167.800 153.365 168.000 155.595 ;
      RECT 167.755 155.595 168.045 155.885 ;
      RECT 152.895 152.960 153.185 153.480 ;
      RECT 172.075 92.155 172.365 92.445 ;
      RECT 172.120 92.445 172.320 114.955 ;
      RECT 172.075 114.955 172.365 115.245 ;
      RECT 172.575 114.840 172.865 115.360 ;
      RECT 173.075 95.275 173.365 95.565 ;
      RECT 173.120 95.565 173.320 116.055 ;
      RECT 173.075 116.055 173.365 116.345 ;
      RECT 172.575 115.940 172.865 116.460 ;
      RECT 152.895 151.860 153.185 152.380 ;
      RECT 168.255 151.860 168.545 152.380 ;
      RECT 153.395 150.395 153.685 150.685 ;
      RECT 153.440 150.685 153.640 153.075 ;
      RECT 153.395 153.075 153.685 153.365 ;
      RECT 109.235 153.075 109.525 153.365 ;
      RECT 109.280 153.365 109.480 155.075 ;
      RECT 109.235 155.075 109.525 155.365 ;
      RECT 102.455 87.995 102.745 88.285 ;
      RECT 102.500 88.285 102.700 108.355 ;
      RECT 102.455 108.355 102.745 108.645 ;
      RECT 137.015 88.515 137.305 88.805 ;
      RECT 137.060 88.805 137.260 108.355 ;
      RECT 137.015 108.355 137.305 108.645 ;
      RECT 108.815 84.120 109.105 84.640 ;
      RECT 103.455 108.240 103.745 108.760 ;
      RECT 138.015 108.240 138.305 108.760 ;
      RECT 109.815 83.315 110.105 83.605 ;
      RECT 109.860 83.605 110.060 85.335 ;
      RECT 109.815 85.335 110.105 85.625 ;
      RECT 108.815 85.220 109.105 85.740 ;
      RECT 97.295 82.795 97.585 83.085 ;
      RECT 97.340 83.085 97.540 86.435 ;
      RECT 97.295 86.435 97.585 86.725 ;
      RECT 102.955 91.635 103.245 91.925 ;
      RECT 103.000 91.925 103.200 114.955 ;
      RECT 102.955 114.955 103.245 115.245 ;
      RECT 137.515 92.155 137.805 92.445 ;
      RECT 137.560 92.445 137.760 114.955 ;
      RECT 137.515 114.955 137.805 115.245 ;
      RECT 137.535 152.960 137.825 153.480 ;
      RECT 103.455 114.840 103.745 115.360 ;
      RECT 138.015 114.840 138.305 115.360 ;
      RECT 107.815 84.235 108.105 84.525 ;
      RECT 107.860 84.525 108.060 87.475 ;
      RECT 107.815 87.475 108.105 87.765 ;
      RECT 103.955 95.795 104.245 96.085 ;
      RECT 104.000 96.085 104.200 116.055 ;
      RECT 103.955 116.055 104.245 116.345 ;
      RECT 138.515 95.275 138.805 95.565 ;
      RECT 138.560 95.565 138.760 116.055 ;
      RECT 138.515 116.055 138.805 116.345 ;
      RECT 104.455 90.595 104.745 90.885 ;
      RECT 104.500 90.885 104.700 107.255 ;
      RECT 104.455 107.255 104.745 107.545 ;
      RECT 103.455 115.940 103.745 116.460 ;
      RECT 138.015 115.940 138.305 116.460 ;
      RECT 139.015 90.075 139.305 90.365 ;
      RECT 139.060 90.365 139.260 107.255 ;
      RECT 139.015 107.255 139.305 107.545 ;
      RECT 122.675 149.355 122.965 149.645 ;
      RECT 122.720 149.645 122.920 151.975 ;
      RECT 122.675 151.975 122.965 152.265 ;
      RECT 108.735 151.860 109.025 152.380 ;
      RECT 122.175 151.860 122.465 152.380 ;
      RECT 137.535 151.860 137.825 152.380 ;
      RECT 108.235 151.975 108.525 152.265 ;
      RECT 108.280 152.265 108.480 155.595 ;
      RECT 108.235 155.595 108.525 155.885 ;
      RECT 103.455 107.140 103.745 107.660 ;
      RECT 121.675 149.875 121.965 150.165 ;
      RECT 121.720 150.165 121.920 153.075 ;
      RECT 121.675 153.075 121.965 153.365 ;
      RECT 138.015 107.140 138.305 107.660 ;
      RECT 108.735 152.960 109.025 153.480 ;
      RECT 122.175 152.960 122.465 153.480 ;
      RECT 138.015 18.800 138.305 19.320 ;
      RECT 108.815 71.220 109.105 71.740 ;
      RECT 103.455 25.400 103.745 25.920 ;
      RECT 103.455 17.700 103.745 18.220 ;
      RECT 137.515 18.915 137.805 19.205 ;
      RECT 137.560 19.205 137.760 42.235 ;
      RECT 137.515 42.235 137.805 42.525 ;
      RECT 137.015 25.515 137.305 25.805 ;
      RECT 137.060 25.805 137.260 44.315 ;
      RECT 137.015 44.315 137.305 44.605 ;
      RECT 102.955 18.915 103.245 19.205 ;
      RECT 103.000 19.205 103.200 42.755 ;
      RECT 102.955 42.755 103.245 43.045 ;
      RECT 102.455 25.515 102.745 25.805 ;
      RECT 102.500 25.805 102.700 43.795 ;
      RECT 102.455 43.795 102.745 44.085 ;
      RECT 138.015 25.400 138.305 25.920 ;
      RECT 138.015 17.700 138.305 18.220 ;
      RECT 103.455 26.500 103.745 27.020 ;
      RECT 139.015 26.615 139.305 26.905 ;
      RECT 139.060 26.905 139.260 44.835 ;
      RECT 139.015 44.835 139.305 45.125 ;
      RECT 108.815 63.520 109.105 64.040 ;
      RECT 129.455 63.520 129.745 64.040 ;
      RECT 129.455 71.220 129.745 71.740 ;
      RECT 104.455 26.615 104.745 26.905 ;
      RECT 104.500 26.905 104.700 45.355 ;
      RECT 104.455 45.355 104.745 45.645 ;
      RECT 97.295 43.795 97.585 44.085 ;
      RECT 97.340 44.085 97.540 46.395 ;
      RECT 97.295 46.395 97.585 46.685 ;
      RECT 97.340 46.685 97.540 47.435 ;
      RECT 97.295 47.435 97.585 47.725 ;
      RECT 138.015 26.500 138.305 27.020 ;
      RECT 109.315 24.555 109.605 24.845 ;
      RECT 109.360 24.845 109.560 48.535 ;
      RECT 109.315 48.535 109.605 48.825 ;
      RECT 108.815 49.520 109.105 50.040 ;
      RECT 138.515 17.815 138.805 18.105 ;
      RECT 138.560 18.105 138.760 38.075 ;
      RECT 138.515 38.075 138.805 38.365 ;
      RECT 130.455 44.315 130.745 44.605 ;
      RECT 130.500 44.605 130.700 63.635 ;
      RECT 130.455 63.635 130.745 63.925 ;
      RECT 108.815 62.420 109.105 62.940 ;
      RECT 129.455 62.420 129.745 62.940 ;
      RECT 108.815 70.120 109.105 70.640 ;
      RECT 129.455 70.120 129.745 70.640 ;
      RECT 130.955 44.835 131.245 45.125 ;
      RECT 131.000 45.125 131.200 62.535 ;
      RECT 130.955 62.535 131.245 62.825 ;
      RECT 108.315 27.675 108.605 27.965 ;
      RECT 108.360 27.965 108.560 49.635 ;
      RECT 108.315 49.635 108.605 49.925 ;
      RECT 108.815 48.420 109.105 48.940 ;
      RECT 103.455 18.800 103.745 19.320 ;
      RECT 103.955 17.815 104.245 18.105 ;
      RECT 104.000 18.105 104.200 37.555 ;
      RECT 103.955 37.555 104.245 37.845 ;
      RECT 175.535 71.220 175.825 71.740 ;
      RECT 144.815 63.520 145.105 64.040 ;
      RECT 160.175 63.520 160.465 64.040 ;
      RECT 175.535 63.520 175.825 64.040 ;
      RECT 159.175 44.315 159.465 44.605 ;
      RECT 159.220 44.605 159.420 63.635 ;
      RECT 159.175 63.635 159.465 63.925 ;
      RECT 173.575 26.615 173.865 26.905 ;
      RECT 173.620 26.905 173.820 44.835 ;
      RECT 173.575 44.835 173.865 45.125 ;
      RECT 173.075 17.815 173.365 18.105 ;
      RECT 173.120 18.105 173.320 38.595 ;
      RECT 173.075 38.595 173.365 38.885 ;
      RECT 172.575 18.800 172.865 19.320 ;
      RECT 144.815 62.420 145.105 62.940 ;
      RECT 174.535 44.315 174.825 44.605 ;
      RECT 174.580 44.605 174.780 63.635 ;
      RECT 174.535 63.635 174.825 63.925 ;
      RECT 144.815 71.220 145.105 71.740 ;
      RECT 145.815 45.355 146.105 45.645 ;
      RECT 145.860 45.645 146.060 62.535 ;
      RECT 145.815 62.535 146.105 62.825 ;
      RECT 172.075 18.915 172.365 19.205 ;
      RECT 172.120 19.205 172.320 41.715 ;
      RECT 172.075 41.715 172.365 42.005 ;
      RECT 160.175 62.420 160.465 62.940 ;
      RECT 172.575 25.400 172.865 25.920 ;
      RECT 175.535 62.420 175.825 62.940 ;
      RECT 161.175 44.835 161.465 45.125 ;
      RECT 161.220 45.125 161.420 62.535 ;
      RECT 161.175 62.535 161.465 62.825 ;
      RECT 171.575 25.515 171.865 25.805 ;
      RECT 171.620 25.805 171.820 44.315 ;
      RECT 171.575 44.315 171.865 44.605 ;
      RECT 176.535 44.835 176.825 45.125 ;
      RECT 176.580 45.125 176.780 62.535 ;
      RECT 176.535 62.535 176.825 62.825 ;
      RECT 144.815 70.120 145.105 70.640 ;
      RECT 160.175 70.120 160.465 70.640 ;
      RECT 175.535 70.120 175.825 70.640 ;
      RECT 172.575 26.500 172.865 27.020 ;
      RECT 143.815 43.795 144.105 44.085 ;
      RECT 143.860 44.085 144.060 63.635 ;
      RECT 143.815 63.635 144.105 63.925 ;
      RECT 160.175 71.220 160.465 71.740 ;
      RECT 172.575 17.700 172.865 18.220 ;
    LAYER Metal5 ;
      RECT 0.000 0.000 189.120 313.040 ;
  END
END sr16_rx4
